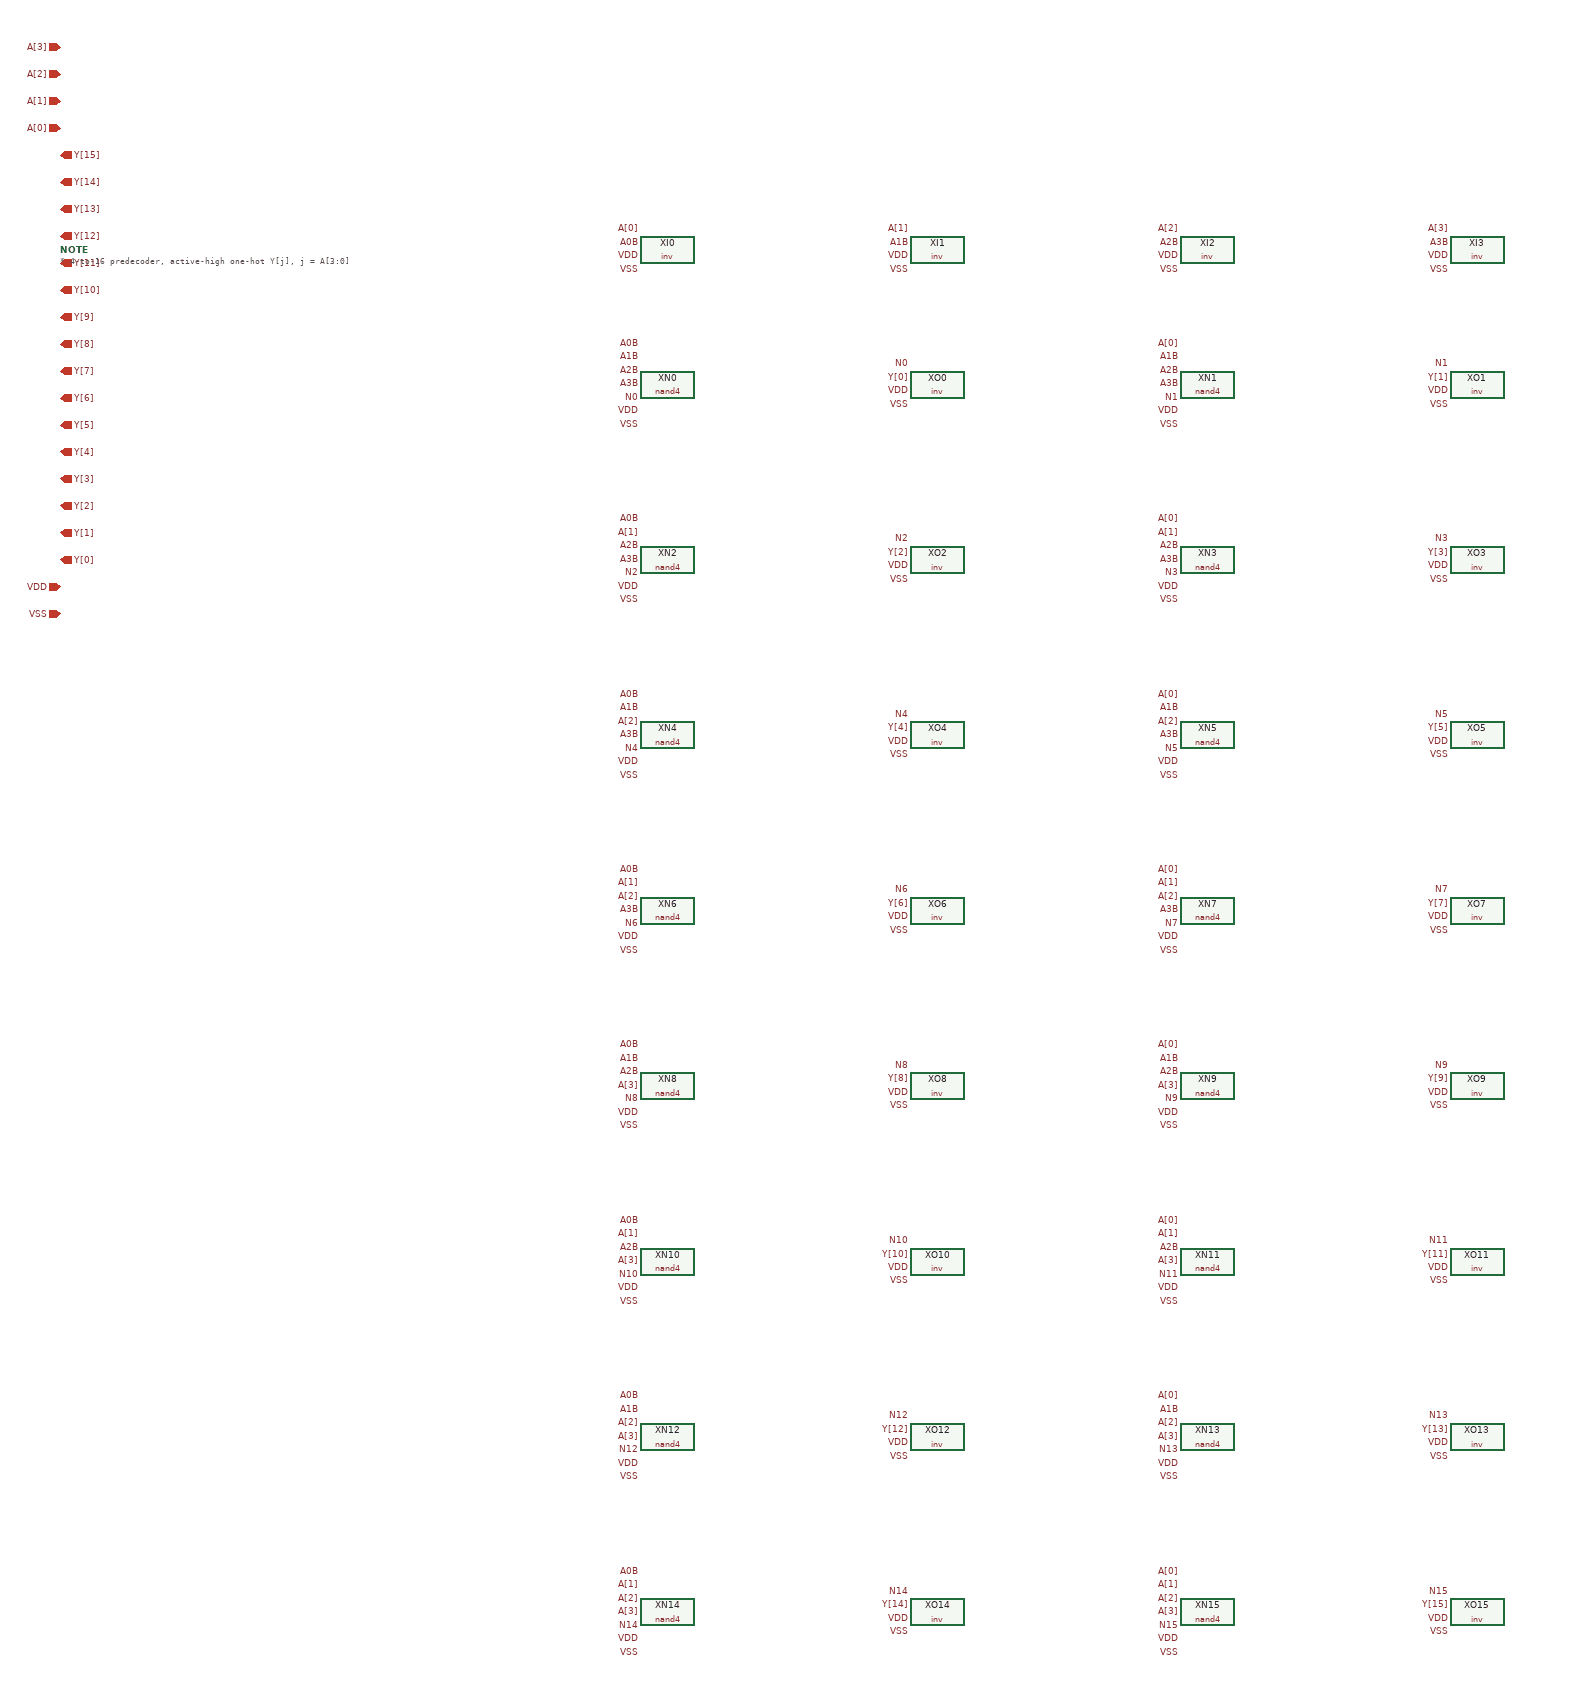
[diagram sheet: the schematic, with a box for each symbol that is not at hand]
v {xschem version=3.4.8RC file_version=1.3}
G {}
K {}
V {}
S {}
E {}
C {gates/inv.sym} 0 0 0 0 {name=XI0}
C {devices/lab_pin.sym} -40.0 -30.0 0 0 {name=l0 lab=A[0]}
C {devices/lab_pin.sym} -40.0 -10.0 0 0 {name=l1 lab=A0B}
C {devices/lab_pin.sym} -40.0 10.0 0 0 {name=l2 lab=VDD}
C {devices/lab_pin.sym} -40.0 30.0 0 0 {name=l3 lab=VSS}
C {gates/inv.sym} 400 0 0 0 {name=XI1}
C {devices/lab_pin.sym} 360.0 -30.0 0 0 {name=l4 lab=A[1]}
C {devices/lab_pin.sym} 360.0 -10.0 0 0 {name=l5 lab=A1B}
C {devices/lab_pin.sym} 360.0 10.0 0 0 {name=l6 lab=VDD}
C {devices/lab_pin.sym} 360.0 30.0 0 0 {name=l7 lab=VSS}
C {gates/inv.sym} 800 0 0 0 {name=XI2}
C {devices/lab_pin.sym} 760.0 -30.0 0 0 {name=l8 lab=A[2]}
C {devices/lab_pin.sym} 760.0 -10.0 0 0 {name=l9 lab=A2B}
C {devices/lab_pin.sym} 760.0 10.0 0 0 {name=l10 lab=VDD}
C {devices/lab_pin.sym} 760.0 30.0 0 0 {name=l11 lab=VSS}
C {gates/inv.sym} 1200 0 0 0 {name=XI3}
C {devices/lab_pin.sym} 1160.0 -30.0 0 0 {name=l12 lab=A[3]}
C {devices/lab_pin.sym} 1160.0 -10.0 0 0 {name=l13 lab=A3B}
C {devices/lab_pin.sym} 1160.0 10.0 0 0 {name=l14 lab=VDD}
C {devices/lab_pin.sym} 1160.0 30.0 0 0 {name=l15 lab=VSS}
C {gates/nand4.sym} 0 200 0 0 {name=XN0}
C {devices/lab_pin.sym} -40.0 140.0 0 0 {name=l16 lab=A0B}
C {devices/lab_pin.sym} -40.0 160.0 0 0 {name=l17 lab=A1B}
C {devices/lab_pin.sym} -40.0 180.0 0 0 {name=l18 lab=A2B}
C {devices/lab_pin.sym} -40.0 200.0 0 0 {name=l19 lab=A3B}
C {devices/lab_pin.sym} -40.0 220.0 0 0 {name=l20 lab=N0}
C {devices/lab_pin.sym} -40.0 240.0 0 0 {name=l21 lab=VDD}
C {devices/lab_pin.sym} -40.0 260.0 0 0 {name=l22 lab=VSS}
C {gates/inv.sym} 400 200 0 0 {name=XO0}
C {devices/lab_pin.sym} 360.0 170.0 0 0 {name=l23 lab=N0}
C {devices/lab_pin.sym} 360.0 190.0 0 0 {name=l24 lab=Y[0]}
C {devices/lab_pin.sym} 360.0 210.0 0 0 {name=l25 lab=VDD}
C {devices/lab_pin.sym} 360.0 230.0 0 0 {name=l26 lab=VSS}
C {gates/nand4.sym} 800 200 0 0 {name=XN1}
C {devices/lab_pin.sym} 760.0 140.0 0 0 {name=l27 lab=A[0]}
C {devices/lab_pin.sym} 760.0 160.0 0 0 {name=l28 lab=A1B}
C {devices/lab_pin.sym} 760.0 180.0 0 0 {name=l29 lab=A2B}
C {devices/lab_pin.sym} 760.0 200.0 0 0 {name=l30 lab=A3B}
C {devices/lab_pin.sym} 760.0 220.0 0 0 {name=l31 lab=N1}
C {devices/lab_pin.sym} 760.0 240.0 0 0 {name=l32 lab=VDD}
C {devices/lab_pin.sym} 760.0 260.0 0 0 {name=l33 lab=VSS}
C {gates/inv.sym} 1200 200 0 0 {name=XO1}
C {devices/lab_pin.sym} 1160.0 170.0 0 0 {name=l34 lab=N1}
C {devices/lab_pin.sym} 1160.0 190.0 0 0 {name=l35 lab=Y[1]}
C {devices/lab_pin.sym} 1160.0 210.0 0 0 {name=l36 lab=VDD}
C {devices/lab_pin.sym} 1160.0 230.0 0 0 {name=l37 lab=VSS}
C {gates/nand4.sym} 0 460 0 0 {name=XN2}
C {devices/lab_pin.sym} -40.0 400.0 0 0 {name=l38 lab=A0B}
C {devices/lab_pin.sym} -40.0 420.0 0 0 {name=l39 lab=A[1]}
C {devices/lab_pin.sym} -40.0 440.0 0 0 {name=l40 lab=A2B}
C {devices/lab_pin.sym} -40.0 460.0 0 0 {name=l41 lab=A3B}
C {devices/lab_pin.sym} -40.0 480.0 0 0 {name=l42 lab=N2}
C {devices/lab_pin.sym} -40.0 500.0 0 0 {name=l43 lab=VDD}
C {devices/lab_pin.sym} -40.0 520.0 0 0 {name=l44 lab=VSS}
C {gates/inv.sym} 400 460 0 0 {name=XO2}
C {devices/lab_pin.sym} 360.0 430.0 0 0 {name=l45 lab=N2}
C {devices/lab_pin.sym} 360.0 450.0 0 0 {name=l46 lab=Y[2]}
C {devices/lab_pin.sym} 360.0 470.0 0 0 {name=l47 lab=VDD}
C {devices/lab_pin.sym} 360.0 490.0 0 0 {name=l48 lab=VSS}
C {gates/nand4.sym} 800 460 0 0 {name=XN3}
C {devices/lab_pin.sym} 760.0 400.0 0 0 {name=l49 lab=A[0]}
C {devices/lab_pin.sym} 760.0 420.0 0 0 {name=l50 lab=A[1]}
C {devices/lab_pin.sym} 760.0 440.0 0 0 {name=l51 lab=A2B}
C {devices/lab_pin.sym} 760.0 460.0 0 0 {name=l52 lab=A3B}
C {devices/lab_pin.sym} 760.0 480.0 0 0 {name=l53 lab=N3}
C {devices/lab_pin.sym} 760.0 500.0 0 0 {name=l54 lab=VDD}
C {devices/lab_pin.sym} 760.0 520.0 0 0 {name=l55 lab=VSS}
C {gates/inv.sym} 1200 460 0 0 {name=XO3}
C {devices/lab_pin.sym} 1160.0 430.0 0 0 {name=l56 lab=N3}
C {devices/lab_pin.sym} 1160.0 450.0 0 0 {name=l57 lab=Y[3]}
C {devices/lab_pin.sym} 1160.0 470.0 0 0 {name=l58 lab=VDD}
C {devices/lab_pin.sym} 1160.0 490.0 0 0 {name=l59 lab=VSS}
C {gates/nand4.sym} 0 720 0 0 {name=XN4}
C {devices/lab_pin.sym} -40.0 660.0 0 0 {name=l60 lab=A0B}
C {devices/lab_pin.sym} -40.0 680.0 0 0 {name=l61 lab=A1B}
C {devices/lab_pin.sym} -40.0 700.0 0 0 {name=l62 lab=A[2]}
C {devices/lab_pin.sym} -40.0 720.0 0 0 {name=l63 lab=A3B}
C {devices/lab_pin.sym} -40.0 740.0 0 0 {name=l64 lab=N4}
C {devices/lab_pin.sym} -40.0 760.0 0 0 {name=l65 lab=VDD}
C {devices/lab_pin.sym} -40.0 780.0 0 0 {name=l66 lab=VSS}
C {gates/inv.sym} 400 720 0 0 {name=XO4}
C {devices/lab_pin.sym} 360.0 690.0 0 0 {name=l67 lab=N4}
C {devices/lab_pin.sym} 360.0 710.0 0 0 {name=l68 lab=Y[4]}
C {devices/lab_pin.sym} 360.0 730.0 0 0 {name=l69 lab=VDD}
C {devices/lab_pin.sym} 360.0 750.0 0 0 {name=l70 lab=VSS}
C {gates/nand4.sym} 800 720 0 0 {name=XN5}
C {devices/lab_pin.sym} 760.0 660.0 0 0 {name=l71 lab=A[0]}
C {devices/lab_pin.sym} 760.0 680.0 0 0 {name=l72 lab=A1B}
C {devices/lab_pin.sym} 760.0 700.0 0 0 {name=l73 lab=A[2]}
C {devices/lab_pin.sym} 760.0 720.0 0 0 {name=l74 lab=A3B}
C {devices/lab_pin.sym} 760.0 740.0 0 0 {name=l75 lab=N5}
C {devices/lab_pin.sym} 760.0 760.0 0 0 {name=l76 lab=VDD}
C {devices/lab_pin.sym} 760.0 780.0 0 0 {name=l77 lab=VSS}
C {gates/inv.sym} 1200 720 0 0 {name=XO5}
C {devices/lab_pin.sym} 1160.0 690.0 0 0 {name=l78 lab=N5}
C {devices/lab_pin.sym} 1160.0 710.0 0 0 {name=l79 lab=Y[5]}
C {devices/lab_pin.sym} 1160.0 730.0 0 0 {name=l80 lab=VDD}
C {devices/lab_pin.sym} 1160.0 750.0 0 0 {name=l81 lab=VSS}
C {gates/nand4.sym} 0 980 0 0 {name=XN6}
C {devices/lab_pin.sym} -40.0 920.0 0 0 {name=l82 lab=A0B}
C {devices/lab_pin.sym} -40.0 940.0 0 0 {name=l83 lab=A[1]}
C {devices/lab_pin.sym} -40.0 960.0 0 0 {name=l84 lab=A[2]}
C {devices/lab_pin.sym} -40.0 980.0 0 0 {name=l85 lab=A3B}
C {devices/lab_pin.sym} -40.0 1000.0 0 0 {name=l86 lab=N6}
C {devices/lab_pin.sym} -40.0 1020.0 0 0 {name=l87 lab=VDD}
C {devices/lab_pin.sym} -40.0 1040.0 0 0 {name=l88 lab=VSS}
C {gates/inv.sym} 400 980 0 0 {name=XO6}
C {devices/lab_pin.sym} 360.0 950.0 0 0 {name=l89 lab=N6}
C {devices/lab_pin.sym} 360.0 970.0 0 0 {name=l90 lab=Y[6]}
C {devices/lab_pin.sym} 360.0 990.0 0 0 {name=l91 lab=VDD}
C {devices/lab_pin.sym} 360.0 1010.0 0 0 {name=l92 lab=VSS}
C {gates/nand4.sym} 800 980 0 0 {name=XN7}
C {devices/lab_pin.sym} 760.0 920.0 0 0 {name=l93 lab=A[0]}
C {devices/lab_pin.sym} 760.0 940.0 0 0 {name=l94 lab=A[1]}
C {devices/lab_pin.sym} 760.0 960.0 0 0 {name=l95 lab=A[2]}
C {devices/lab_pin.sym} 760.0 980.0 0 0 {name=l96 lab=A3B}
C {devices/lab_pin.sym} 760.0 1000.0 0 0 {name=l97 lab=N7}
C {devices/lab_pin.sym} 760.0 1020.0 0 0 {name=l98 lab=VDD}
C {devices/lab_pin.sym} 760.0 1040.0 0 0 {name=l99 lab=VSS}
C {gates/inv.sym} 1200 980 0 0 {name=XO7}
C {devices/lab_pin.sym} 1160.0 950.0 0 0 {name=l100 lab=N7}
C {devices/lab_pin.sym} 1160.0 970.0 0 0 {name=l101 lab=Y[7]}
C {devices/lab_pin.sym} 1160.0 990.0 0 0 {name=l102 lab=VDD}
C {devices/lab_pin.sym} 1160.0 1010.0 0 0 {name=l103 lab=VSS}
C {gates/nand4.sym} 0 1240 0 0 {name=XN8}
C {devices/lab_pin.sym} -40.0 1180.0 0 0 {name=l104 lab=A0B}
C {devices/lab_pin.sym} -40.0 1200.0 0 0 {name=l105 lab=A1B}
C {devices/lab_pin.sym} -40.0 1220.0 0 0 {name=l106 lab=A2B}
C {devices/lab_pin.sym} -40.0 1240.0 0 0 {name=l107 lab=A[3]}
C {devices/lab_pin.sym} -40.0 1260.0 0 0 {name=l108 lab=N8}
C {devices/lab_pin.sym} -40.0 1280.0 0 0 {name=l109 lab=VDD}
C {devices/lab_pin.sym} -40.0 1300.0 0 0 {name=l110 lab=VSS}
C {gates/inv.sym} 400 1240 0 0 {name=XO8}
C {devices/lab_pin.sym} 360.0 1210.0 0 0 {name=l111 lab=N8}
C {devices/lab_pin.sym} 360.0 1230.0 0 0 {name=l112 lab=Y[8]}
C {devices/lab_pin.sym} 360.0 1250.0 0 0 {name=l113 lab=VDD}
C {devices/lab_pin.sym} 360.0 1270.0 0 0 {name=l114 lab=VSS}
C {gates/nand4.sym} 800 1240 0 0 {name=XN9}
C {devices/lab_pin.sym} 760.0 1180.0 0 0 {name=l115 lab=A[0]}
C {devices/lab_pin.sym} 760.0 1200.0 0 0 {name=l116 lab=A1B}
C {devices/lab_pin.sym} 760.0 1220.0 0 0 {name=l117 lab=A2B}
C {devices/lab_pin.sym} 760.0 1240.0 0 0 {name=l118 lab=A[3]}
C {devices/lab_pin.sym} 760.0 1260.0 0 0 {name=l119 lab=N9}
C {devices/lab_pin.sym} 760.0 1280.0 0 0 {name=l120 lab=VDD}
C {devices/lab_pin.sym} 760.0 1300.0 0 0 {name=l121 lab=VSS}
C {gates/inv.sym} 1200 1240 0 0 {name=XO9}
C {devices/lab_pin.sym} 1160.0 1210.0 0 0 {name=l122 lab=N9}
C {devices/lab_pin.sym} 1160.0 1230.0 0 0 {name=l123 lab=Y[9]}
C {devices/lab_pin.sym} 1160.0 1250.0 0 0 {name=l124 lab=VDD}
C {devices/lab_pin.sym} 1160.0 1270.0 0 0 {name=l125 lab=VSS}
C {gates/nand4.sym} 0 1500 0 0 {name=XN10}
C {devices/lab_pin.sym} -40.0 1440.0 0 0 {name=l126 lab=A0B}
C {devices/lab_pin.sym} -40.0 1460.0 0 0 {name=l127 lab=A[1]}
C {devices/lab_pin.sym} -40.0 1480.0 0 0 {name=l128 lab=A2B}
C {devices/lab_pin.sym} -40.0 1500.0 0 0 {name=l129 lab=A[3]}
C {devices/lab_pin.sym} -40.0 1520.0 0 0 {name=l130 lab=N10}
C {devices/lab_pin.sym} -40.0 1540.0 0 0 {name=l131 lab=VDD}
C {devices/lab_pin.sym} -40.0 1560.0 0 0 {name=l132 lab=VSS}
C {gates/inv.sym} 400 1500 0 0 {name=XO10}
C {devices/lab_pin.sym} 360.0 1470.0 0 0 {name=l133 lab=N10}
C {devices/lab_pin.sym} 360.0 1490.0 0 0 {name=l134 lab=Y[10]}
C {devices/lab_pin.sym} 360.0 1510.0 0 0 {name=l135 lab=VDD}
C {devices/lab_pin.sym} 360.0 1530.0 0 0 {name=l136 lab=VSS}
C {gates/nand4.sym} 800 1500 0 0 {name=XN11}
C {devices/lab_pin.sym} 760.0 1440.0 0 0 {name=l137 lab=A[0]}
C {devices/lab_pin.sym} 760.0 1460.0 0 0 {name=l138 lab=A[1]}
C {devices/lab_pin.sym} 760.0 1480.0 0 0 {name=l139 lab=A2B}
C {devices/lab_pin.sym} 760.0 1500.0 0 0 {name=l140 lab=A[3]}
C {devices/lab_pin.sym} 760.0 1520.0 0 0 {name=l141 lab=N11}
C {devices/lab_pin.sym} 760.0 1540.0 0 0 {name=l142 lab=VDD}
C {devices/lab_pin.sym} 760.0 1560.0 0 0 {name=l143 lab=VSS}
C {gates/inv.sym} 1200 1500 0 0 {name=XO11}
C {devices/lab_pin.sym} 1160.0 1470.0 0 0 {name=l144 lab=N11}
C {devices/lab_pin.sym} 1160.0 1490.0 0 0 {name=l145 lab=Y[11]}
C {devices/lab_pin.sym} 1160.0 1510.0 0 0 {name=l146 lab=VDD}
C {devices/lab_pin.sym} 1160.0 1530.0 0 0 {name=l147 lab=VSS}
C {gates/nand4.sym} 0 1760 0 0 {name=XN12}
C {devices/lab_pin.sym} -40.0 1700.0 0 0 {name=l148 lab=A0B}
C {devices/lab_pin.sym} -40.0 1720.0 0 0 {name=l149 lab=A1B}
C {devices/lab_pin.sym} -40.0 1740.0 0 0 {name=l150 lab=A[2]}
C {devices/lab_pin.sym} -40.0 1760.0 0 0 {name=l151 lab=A[3]}
C {devices/lab_pin.sym} -40.0 1780.0 0 0 {name=l152 lab=N12}
C {devices/lab_pin.sym} -40.0 1800.0 0 0 {name=l153 lab=VDD}
C {devices/lab_pin.sym} -40.0 1820.0 0 0 {name=l154 lab=VSS}
C {gates/inv.sym} 400 1760 0 0 {name=XO12}
C {devices/lab_pin.sym} 360.0 1730.0 0 0 {name=l155 lab=N12}
C {devices/lab_pin.sym} 360.0 1750.0 0 0 {name=l156 lab=Y[12]}
C {devices/lab_pin.sym} 360.0 1770.0 0 0 {name=l157 lab=VDD}
C {devices/lab_pin.sym} 360.0 1790.0 0 0 {name=l158 lab=VSS}
C {gates/nand4.sym} 800 1760 0 0 {name=XN13}
C {devices/lab_pin.sym} 760.0 1700.0 0 0 {name=l159 lab=A[0]}
C {devices/lab_pin.sym} 760.0 1720.0 0 0 {name=l160 lab=A1B}
C {devices/lab_pin.sym} 760.0 1740.0 0 0 {name=l161 lab=A[2]}
C {devices/lab_pin.sym} 760.0 1760.0 0 0 {name=l162 lab=A[3]}
C {devices/lab_pin.sym} 760.0 1780.0 0 0 {name=l163 lab=N13}
C {devices/lab_pin.sym} 760.0 1800.0 0 0 {name=l164 lab=VDD}
C {devices/lab_pin.sym} 760.0 1820.0 0 0 {name=l165 lab=VSS}
C {gates/inv.sym} 1200 1760 0 0 {name=XO13}
C {devices/lab_pin.sym} 1160.0 1730.0 0 0 {name=l166 lab=N13}
C {devices/lab_pin.sym} 1160.0 1750.0 0 0 {name=l167 lab=Y[13]}
C {devices/lab_pin.sym} 1160.0 1770.0 0 0 {name=l168 lab=VDD}
C {devices/lab_pin.sym} 1160.0 1790.0 0 0 {name=l169 lab=VSS}
C {gates/nand4.sym} 0 2020 0 0 {name=XN14}
C {devices/lab_pin.sym} -40.0 1960.0 0 0 {name=l170 lab=A0B}
C {devices/lab_pin.sym} -40.0 1980.0 0 0 {name=l171 lab=A[1]}
C {devices/lab_pin.sym} -40.0 2000.0 0 0 {name=l172 lab=A[2]}
C {devices/lab_pin.sym} -40.0 2020.0 0 0 {name=l173 lab=A[3]}
C {devices/lab_pin.sym} -40.0 2040.0 0 0 {name=l174 lab=N14}
C {devices/lab_pin.sym} -40.0 2060.0 0 0 {name=l175 lab=VDD}
C {devices/lab_pin.sym} -40.0 2080.0 0 0 {name=l176 lab=VSS}
C {gates/inv.sym} 400 2020 0 0 {name=XO14}
C {devices/lab_pin.sym} 360.0 1990.0 0 0 {name=l177 lab=N14}
C {devices/lab_pin.sym} 360.0 2010.0 0 0 {name=l178 lab=Y[14]}
C {devices/lab_pin.sym} 360.0 2030.0 0 0 {name=l179 lab=VDD}
C {devices/lab_pin.sym} 360.0 2050.0 0 0 {name=l180 lab=VSS}
C {gates/nand4.sym} 800 2020 0 0 {name=XN15}
C {devices/lab_pin.sym} 760.0 1960.0 0 0 {name=l181 lab=A[0]}
C {devices/lab_pin.sym} 760.0 1980.0 0 0 {name=l182 lab=A[1]}
C {devices/lab_pin.sym} 760.0 2000.0 0 0 {name=l183 lab=A[2]}
C {devices/lab_pin.sym} 760.0 2020.0 0 0 {name=l184 lab=A[3]}
C {devices/lab_pin.sym} 760.0 2040.0 0 0 {name=l185 lab=N15}
C {devices/lab_pin.sym} 760.0 2060.0 0 0 {name=l186 lab=VDD}
C {devices/lab_pin.sym} 760.0 2080.0 0 0 {name=l187 lab=VSS}
C {gates/inv.sym} 1200 2020 0 0 {name=XO15}
C {devices/lab_pin.sym} 1160.0 1990.0 0 0 {name=l188 lab=N15}
C {devices/lab_pin.sym} 1160.0 2010.0 0 0 {name=l189 lab=Y[15]}
C {devices/lab_pin.sym} 1160.0 2030.0 0 0 {name=l190 lab=VDD}
C {devices/lab_pin.sym} 1160.0 2050.0 0 0 {name=l191 lab=VSS}
C {devices/ipin.sym} -900 -300 0 0 {name=p192 lab=A[3]}
C {devices/ipin.sym} -900 -260 0 0 {name=p193 lab=A[2]}
C {devices/ipin.sym} -900 -220 0 0 {name=p194 lab=A[1]}
C {devices/ipin.sym} -900 -180 0 0 {name=p195 lab=A[0]}
C {devices/opin.sym} -900 -140 0 0 {name=p196 lab=Y[15]}
C {devices/opin.sym} -900 -100 0 0 {name=p197 lab=Y[14]}
C {devices/opin.sym} -900 -60 0 0 {name=p198 lab=Y[13]}
C {devices/opin.sym} -900 -20 0 0 {name=p199 lab=Y[12]}
C {devices/opin.sym} -900 20 0 0 {name=p200 lab=Y[11]}
C {devices/opin.sym} -900 60 0 0 {name=p201 lab=Y[10]}
C {devices/opin.sym} -900 100 0 0 {name=p202 lab=Y[9]}
C {devices/opin.sym} -900 140 0 0 {name=p203 lab=Y[8]}
C {devices/opin.sym} -900 180 0 0 {name=p204 lab=Y[7]}
C {devices/opin.sym} -900 220 0 0 {name=p205 lab=Y[6]}
C {devices/opin.sym} -900 260 0 0 {name=p206 lab=Y[5]}
C {devices/opin.sym} -900 300 0 0 {name=p207 lab=Y[4]}
C {devices/opin.sym} -900 340 0 0 {name=p208 lab=Y[3]}
C {devices/opin.sym} -900 380 0 0 {name=p209 lab=Y[2]}
C {devices/opin.sym} -900 420 0 0 {name=p210 lab=Y[1]}
C {devices/opin.sym} -900 460 0 0 {name=p211 lab=Y[0]}
C {devices/iopin.sym} -900 500 0 0 {name=p212 lab=VDD}
C {devices/iopin.sym} -900 540 0 0 {name=p213 lab=VSS}
C {devices/code_shown.sym} -900 0 0 0 {name=NOTE only_toplevel=false
place=header
value="* 4-to-16 predecoder, active-high one-hot Y[j], j = A[3:0]"}
